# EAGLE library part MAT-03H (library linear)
Dual TRANSISTOR

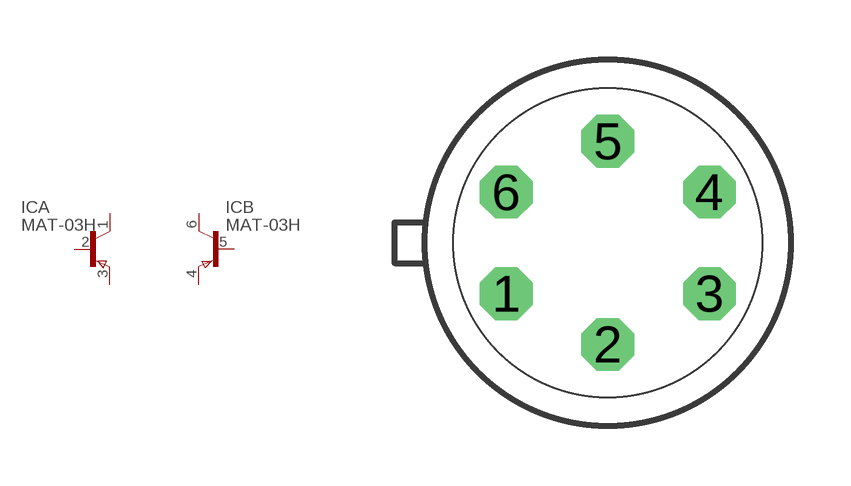
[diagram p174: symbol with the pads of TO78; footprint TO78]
Designator prefix IC; gates A=PNP-L B=PNP-R

## MAT-03H  [TO78]
1  A:C  pas
2  A:B  pas
3  A:E  pas
4  B:E  pas
5  B:B  pas
6  B:C  pas

## Footprint TO78 (pad centres in mm)
Metal Can Package
drill 0.813 octagon: 1 -2.54,-1.27; 2 0,-2.54; 3 2.54,-1.27; 4 2.54,1.27; 5 0,2.54; 6 -2.54,1.27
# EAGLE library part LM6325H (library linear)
BUFFER

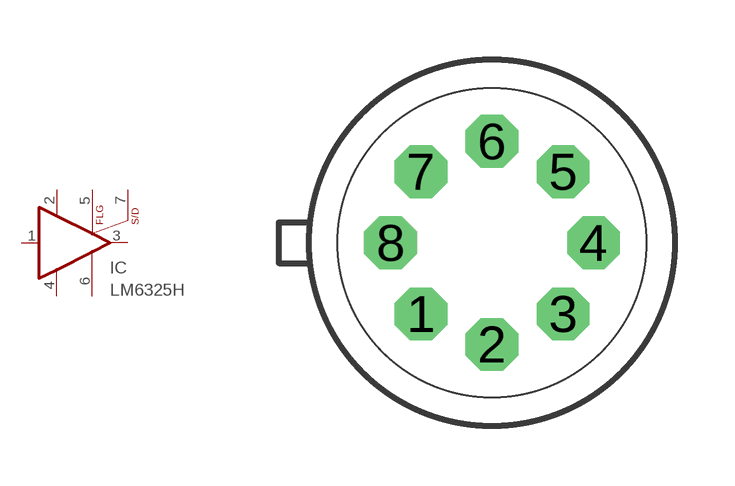
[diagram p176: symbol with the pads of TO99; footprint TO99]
Designator prefix IC

## LM6325H  [TO99]
1  IN  in
2  V+  pwr
3  OUT  out
4  V-  pwr
5  FLG
6  GND  pwr
7  S/D

## Footprint TO99 (pad centres in mm)
Metal Can Package
drill 0.813 octagon: 1 -1.778,-1.778; 2 0,-2.54; 3 1.778,-1.778; 4 2.54,0; 5 1.778,1.778; 6 0,2.54; 7 -1.778,1.778; 8 -2.54,0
